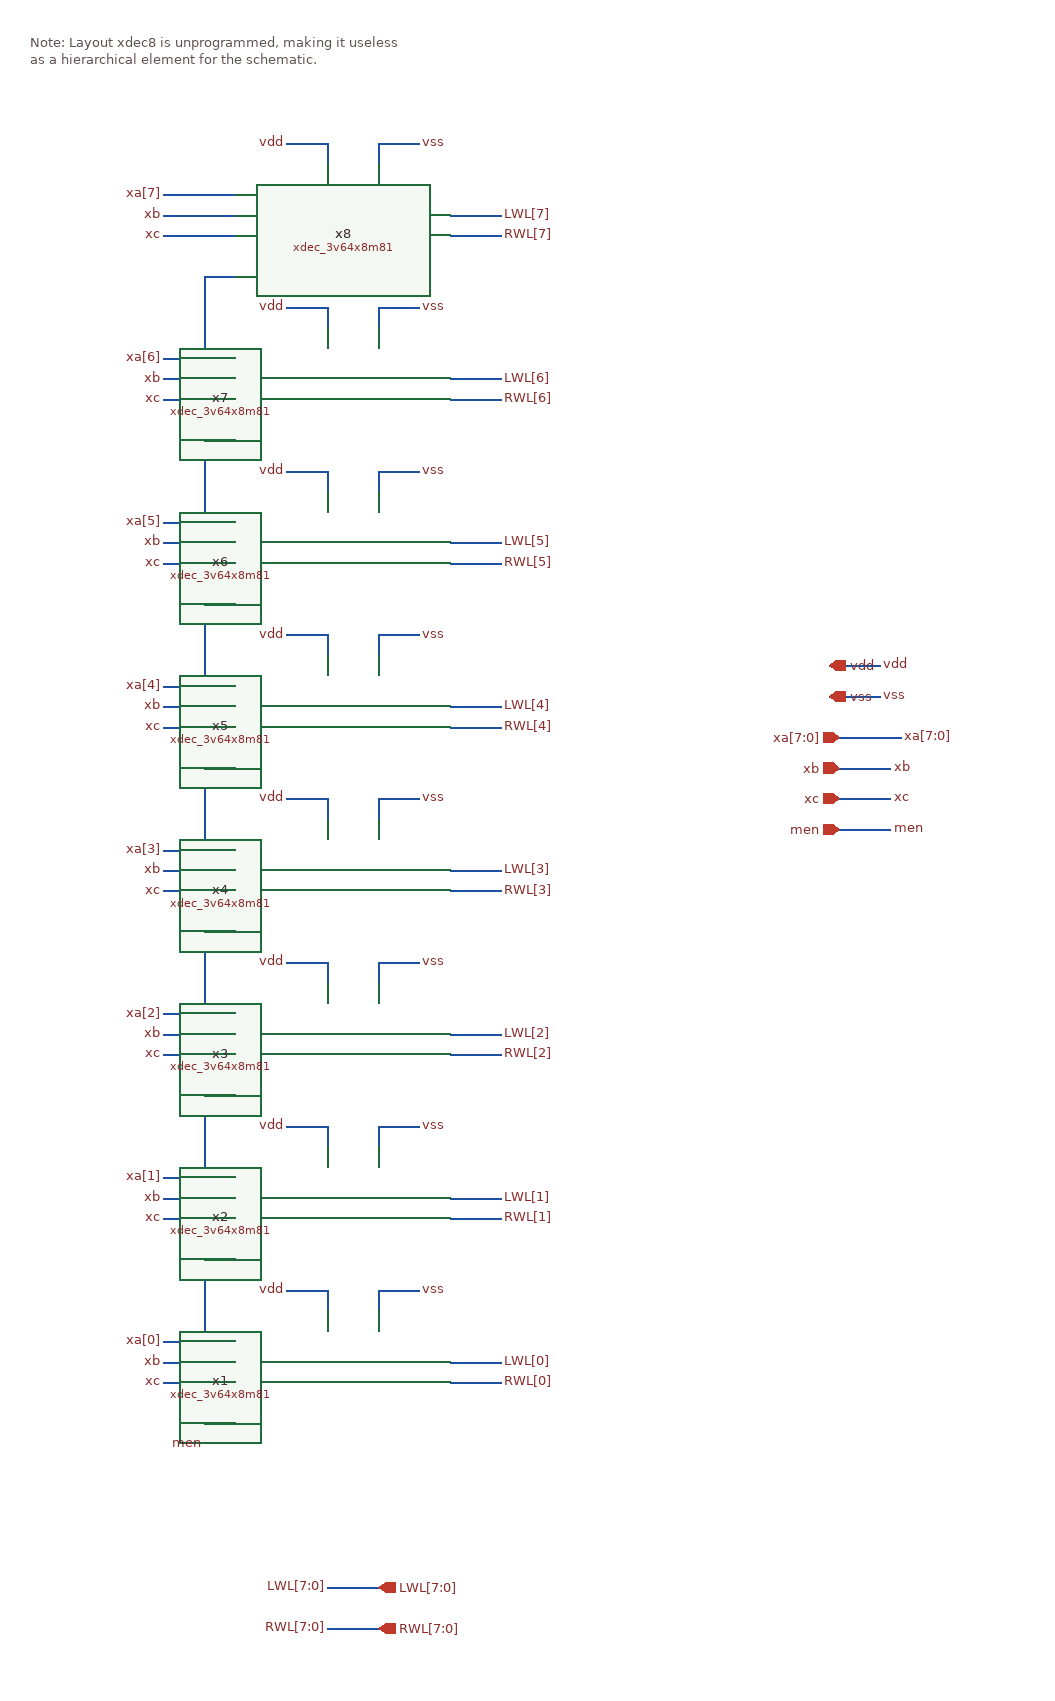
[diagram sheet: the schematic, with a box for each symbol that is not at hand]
v {xschem version=3.4.6 file_version=1.2}
G {}
K {}
V {}
S {}
E {}
T {Note:  Layout xdec8 is unprogrammed, making it useless
as a hierarchical element for the schematic.} -200 -1260 0 0 0.4 0.4 {}
N 50 -30 90 -30 {lab=vdd}
N 140 -30 180 -30 {lab=vss}
N 90 -30 90 -10 {lab=vdd}
N 140 -30 140 -10 {lab=vss}
N 50 -190 90 -190 {lab=vdd}
N 140 -190 180 -190 {lab=vss}
N 90 -190 90 -170 {lab=vdd}
N 140 -190 140 -170 {lab=vss}
N 50 -350 90 -350 {lab=vdd}
N 140 -350 180 -350 {lab=vss}
N 90 -350 90 -330 {lab=vdd}
N 140 -350 140 -330 {lab=vss}
N 50 -510 90 -510 {lab=vdd}
N 140 -510 180 -510 {lab=vss}
N 90 -510 90 -490 {lab=vdd}
N 140 -510 140 -490 {lab=vss}
N 50 -670 90 -670 {lab=vdd}
N 140 -670 180 -670 {lab=vss}
N 90 -670 90 -650 {lab=vdd}
N 140 -670 140 -650 {lab=vss}
N 50 -830 90 -830 {lab=vdd}
N 140 -830 180 -830 {lab=vss}
N 90 -830 90 -810 {lab=vdd}
N 140 -830 140 -810 {lab=vss}
N 50 -990 90 -990 {lab=vdd}
N 140 -990 180 -990 {lab=vss}
N 90 -990 90 -970 {lab=vdd}
N 140 -990 140 -970 {lab=vss}
N 50 -1150 90 -1150 {lab=vdd}
N 140 -1150 180 -1150 {lab=vss}
N 90 -1150 90 -1130 {lab=vdd}
N 140 -1150 140 -1130 {lab=vss}
N 210 -1080 260 -1080 {lab=LWL[7]}
N 210 -1060 260 -1060 {lab=RWL[7]}
N -30 -1020 -0 -1020 {lab=men}
N 210 -920 260 -920 {lab=LWL[6]}
N 210 -900 260 -900 {lab=RWL[6]}
N -30 -860 0 -860 {lab=men}
N 210 -600 260 -600 {lab=LWL[4]}
N 210 -580 260 -580 {lab=RWL[4]}
N -30 -540 0 -540 {lab=men}
N 210 -760 260 -760 {lab=LWL[5]}
N 210 -740 260 -740 {lab=RWL[5]}
N -30 -700 0 -700 {lab=men}
N 210 -440 260 -440 {lab=LWL[3]}
N 210 -420 260 -420 {lab=RWL[3]}
N -30 -380 0 -380 {lab=men}
N 210 -280 260 -280 {lab=LWL[2]}
N 210 -260 260 -260 {lab=RWL[2]}
N -30 -220 0 -220 {lab=men}
N 210 40 260 40 {lab=LWL[0]}
N 210 60 260 60 {lab=RWL[0]}
N -30 100 0 100 {lab=men}
N 210 -120 260 -120 {lab=LWL[1]}
N 210 -100 260 -100 {lab=RWL[1]}
N -30 -60 0 -60 {lab=men}
N -30 -1020 -30 120 {lab=men}
N 590 -570 650 -570 {lab=xa[7:0]}
N 590 -540 640 -540 {lab=xb}
N 590 -510 640 -510 {lab=xc}
N 580 -640 630 -640 {lab=vdd}
N 580 -610 630 -610 {lab=vss}
N 90 260 140 260 {lab=LWL[7:0]}
N 90 300 140 300 {lab=RWL[7:0]}
N 590 -480 640 -480 {lab=men}
N -70 20 -0 20 {lab=xa[0]}
N -70 -140 0 -140 {lab=xa[1]}
N -70 -300 0 -300 {lab=xa[2]}
N -70 -460 0 -460 {lab=xa[3]}
N -70 -620 0 -620 {lab=xa[4]}
N -70 -780 0 -780 {lab=xa[5]}
N -70 -940 0 -940 {lab=xa[6]}
N -70 -1100 0 -1100 {lab=xa[7]}
N -70 60 -0 60 {lab=xc}
N -70 40 -0 40 {lab=xb[0]}
N -70 -100 0 -100 {lab=xc}
N -70 -120 0 -120 {lab=xb}
N -70 -260 0 -260 {lab=xc}
N -70 -280 0 -280 {lab=xb}
N -70 -420 0 -420 {lab=xc}
N -70 -440 0 -440 {lab=xb}
N -70 -580 0 -580 {lab=xc}
N -70 -600 0 -600 {lab=xb}
N -70 -740 0 -740 {lab=xc}
N -70 -760 0 -760 {lab=xb}
N -70 -900 0 -900 {lab=xc}
N -70 -920 0 -920 {lab=xb}
N -70 -1060 0 -1060 {lab=xc}
N -70 -1080 0 -1080 {lab=xb}
C {xdec_3v64x8m81.sym} 150 50 0 0 {name=x1}
C {xdec_3v64x8m81.sym} 150 -110 0 0 {name=x2}
C {xdec_3v64x8m81.sym} 150 -270 0 0 {name=x3}
C {xdec_3v64x8m81.sym} 150 -430 0 0 {name=x4}
C {xdec_3v64x8m81.sym} 150 -590 0 0 {name=x5}
C {xdec_3v64x8m81.sym} 150 -750 0 0 {name=x6}
C {xdec_3v64x8m81.sym} 150 -910 0 0 {name=x7}
C {xdec_3v64x8m81.sym} 150 -1070 0 0 {name=x8}
C {lab_pin.sym} 50 -30 0 0 {name=p1 sig_type=std_logic lab=vdd}
C {lab_pin.sym} 50 -190 0 0 {name=p3 sig_type=std_logic lab=vdd}
C {lab_pin.sym} 50 -350 0 0 {name=p5 sig_type=std_logic lab=vdd}
C {lab_pin.sym} 50 -510 0 0 {name=p7 sig_type=std_logic lab=vdd}
C {lab_pin.sym} 50 -670 0 0 {name=p9 sig_type=std_logic lab=vdd}
C {lab_pin.sym} 50 -830 0 0 {name=p11 sig_type=std_logic lab=vdd}
C {lab_pin.sym} 50 -990 0 0 {name=p13 sig_type=std_logic lab=vdd}
C {lab_pin.sym} 50 -1150 0 0 {name=p15 sig_type=std_logic lab=vdd}
C {ipin.sym} 590 -570 0 0 {name=p65 lab=xa[7:0]}
C {lab_pin.sym} 650 -570 0 1 {name=p66 sig_type=std_logic lab=xa[7:0]}
C {ipin.sym} 590 -540 0 0 {name=p67 lab=xb}
C {lab_pin.sym} 640 -540 0 1 {name=p68 sig_type=std_logic lab=xb}
C {ipin.sym} 590 -510 0 0 {name=p69 lab=xc}
C {lab_pin.sym} 640 -510 0 1 {name=p70 sig_type=std_logic lab=xc}
C {iopin.sym} 580 -640 0 1 {name=p71 lab=vdd}
C {lab_pin.sym} 630 -640 0 1 {name=p72 sig_type=std_logic lab=vdd}
C {iopin.sym} 580 -610 0 1 {name=p73 lab=vss}
C {lab_pin.sym} 630 -610 0 1 {name=p74 sig_type=std_logic lab=vss}
C {opin.sym} 140 300 0 0 {name=p75 lab=RWL[7:0]}
C {opin.sym} 140 260 0 0 {name=p76 lab=LWL[7:0]}
C {lab_pin.sym} 90 260 0 0 {name=p77 sig_type=std_logic lab=LWL[7:0]}
C {lab_pin.sym} 90 300 0 0 {name=p78 sig_type=std_logic lab=RWL[7:0]}
C {lab_pin.sym} 260 40 0 1 {name=p79 sig_type=std_logic lab=LWL[0]}
C {lab_pin.sym} 260 60 0 1 {name=p80 sig_type=std_logic lab=RWL[0]}
C {lab_pin.sym} 260 -120 0 1 {name=p81 sig_type=std_logic lab=LWL[1]}
C {lab_pin.sym} 260 -100 0 1 {name=p82 sig_type=std_logic lab=RWL[1]}
C {lab_pin.sym} 260 -280 0 1 {name=p83 sig_type=std_logic lab=LWL[2]}
C {lab_pin.sym} 260 -260 0 1 {name=p84 sig_type=std_logic lab=RWL[2]}
C {lab_pin.sym} 260 -440 0 1 {name=p85 sig_type=std_logic lab=LWL[3]}
C {lab_pin.sym} 260 -420 0 1 {name=p86 sig_type=std_logic lab=RWL[3]}
C {lab_pin.sym} 260 -600 0 1 {name=p87 sig_type=std_logic lab=LWL[4]}
C {lab_pin.sym} 260 -580 0 1 {name=p88 sig_type=std_logic lab=RWL[4]}
C {lab_pin.sym} 260 -760 0 1 {name=p89 sig_type=std_logic lab=LWL[5]}
C {lab_pin.sym} 260 -740 0 1 {name=p90 sig_type=std_logic lab=RWL[5]}
C {lab_pin.sym} 260 -920 0 1 {name=p91 sig_type=std_logic lab=LWL[6]}
C {lab_pin.sym} 260 -900 0 1 {name=p92 sig_type=std_logic lab=RWL[6]}
C {lab_pin.sym} 260 -1080 0 1 {name=p93 sig_type=std_logic lab=LWL[7]}
C {lab_pin.sym} 260 -1060 0 1 {name=p94 sig_type=std_logic lab=RWL[7]}
C {ipin.sym} 590 -480 0 0 {name=p143 lab=men}
C {lab_pin.sym} 640 -480 0 1 {name=p144 sig_type=std_logic lab=men}
C {lab_pin.sym} -30 120 1 1 {name=p145 sig_type=std_logic lab=men}
C {lab_pin.sym} -70 20 0 0 {name=p149 sig_type=std_logic lab=xa[0]}
C {lab_pin.sym} -70 -140 0 0 {name=p150 sig_type=std_logic lab=xa[1]}
C {lab_pin.sym} -70 -300 0 0 {name=p151 sig_type=std_logic lab=xa[2]}
C {lab_pin.sym} -70 -460 0 0 {name=p152 sig_type=std_logic lab=xa[3]}
C {lab_pin.sym} -70 -620 0 0 {name=p153 sig_type=std_logic lab=xa[4]}
C {lab_pin.sym} -70 -780 0 0 {name=p154 sig_type=std_logic lab=xa[5]}
C {lab_pin.sym} -70 -940 0 0 {name=p155 sig_type=std_logic lab=xa[6]}
C {lab_pin.sym} -70 -1100 0 0 {name=p156 sig_type=std_logic lab=xa[7]}
C {lab_pin.sym} -70 40 0 0 {name=p181 sig_type=std_logic lab=xb}
C {lab_pin.sym} -70 60 0 0 {name=p182 sig_type=std_logic lab=xc}
C {lab_pin.sym} -70 -120 0 0 {name=p183 sig_type=std_logic lab=xb}
C {lab_pin.sym} -70 -100 0 0 {name=p184 sig_type=std_logic lab=xc}
C {lab_pin.sym} -70 -280 0 0 {name=p185 sig_type=std_logic lab=xb}
C {lab_pin.sym} -70 -260 0 0 {name=p186 sig_type=std_logic lab=xc}
C {lab_pin.sym} -70 -440 0 0 {name=p187 sig_type=std_logic lab=xb}
C {lab_pin.sym} -70 -420 0 0 {name=p188 sig_type=std_logic lab=xc}
C {lab_pin.sym} -70 -600 0 0 {name=p189 sig_type=std_logic lab=xb}
C {lab_pin.sym} -70 -580 0 0 {name=p190 sig_type=std_logic lab=xc}
C {lab_pin.sym} -70 -760 0 0 {name=p191 sig_type=std_logic lab=xb}
C {lab_pin.sym} -70 -740 0 0 {name=p192 sig_type=std_logic lab=xc}
C {lab_pin.sym} -70 -920 0 0 {name=p193 sig_type=std_logic lab=xb}
C {lab_pin.sym} -70 -900 0 0 {name=p194 sig_type=std_logic lab=xc}
C {lab_pin.sym} -70 -1080 0 0 {name=p195 sig_type=std_logic lab=xb}
C {lab_pin.sym} -70 -1060 0 0 {name=p196 sig_type=std_logic lab=xc}
C {lab_pin.sym} 180 -1150 0 1 {name=p2 sig_type=std_logic lab=vss}
C {lab_pin.sym} 180 -990 0 1 {name=p4 sig_type=std_logic lab=vss}
C {lab_pin.sym} 180 -830 0 1 {name=p6 sig_type=std_logic lab=vss}
C {lab_pin.sym} 180 -670 0 1 {name=p8 sig_type=std_logic lab=vss}
C {lab_pin.sym} 180 -510 0 1 {name=p10 sig_type=std_logic lab=vss}
C {lab_pin.sym} 180 -350 0 1 {name=p12 sig_type=std_logic lab=vss}
C {lab_pin.sym} 180 -190 0 1 {name=p14 sig_type=std_logic lab=vss}
C {lab_pin.sym} 180 -30 0 1 {name=p16 sig_type=std_logic lab=vss}
